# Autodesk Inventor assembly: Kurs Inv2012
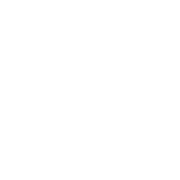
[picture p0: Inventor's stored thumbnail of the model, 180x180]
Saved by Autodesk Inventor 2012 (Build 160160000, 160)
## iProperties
Created: 2010-03
Part Number: Kurs Inv2012
Document SubType Name: Assembly
Designer: Johan Wedeen
Manufacturer: Standard
Standards Organization: Custom
Author: Johan Wedeen
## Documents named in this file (1)
- C:\Program Files\Autodesk\Inventor 2012\Templates\InventorKurs\Kurs Inv2012.iam
